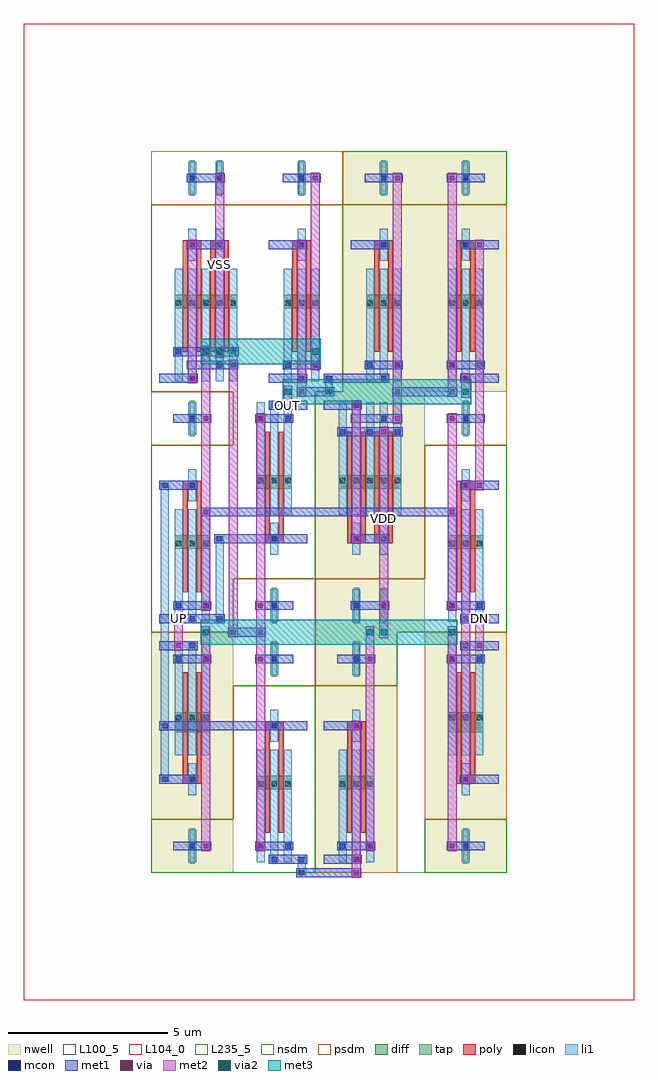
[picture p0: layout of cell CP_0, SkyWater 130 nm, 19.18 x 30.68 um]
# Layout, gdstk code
from math import pi, radians
import gdstk
lib = gdstk.Library(unit=1e-6, precision=1e-09)
def R(c, l, rs):  # rectangles x0, y0, x1, y1
    for r in rs: c.add(gdstk.rectangle(r[:2], r[2:], *l))
def A(c, l, x, y, w, h, nx, ny, dx, dy):  # array of equal rectangles
    R(c, l, [(x+i*dx, y+j*dy, x+i*dx+w, y+j*dy+h) for i in range(nx) for j in range(ny)])
def P(c, l, *ps):  # polygons
    for p in ps: c.add(gdstk.Polygon(p, *l))
nwell = (64, 20)
diff = (65, 20)
tap = (65, 44)
poly = (66, 20)
licon = (66, 44)
li1 = (67, 20)
mcon = (67, 44)
met1 = (68, 20)
via = (68, 44)
met2 = (69, 20)
via2 = (69, 44)
met3 = (70, 20)
nsdm = (93, 44)
psdm = (94, 20)
L100_5 = (100, 5)
L104_0 = (104, 0)
L235_5 = (235, 5)

scm_nmos_16357927_x1_y1_ = lib.new_cell('SCM_NMOS_16357927_X1_Y1_1668766171')
R(scm_nmos_16357927_x1_y1_, diff, [(0.735,2.625,2.705,3.045)])
R(scm_nmos_16357927_x1_y1_, tap, [(1.205,6.16,1.375,7.28), (2.065,6.16,2.235,7.28)])
A(scm_nmos_16357927_x1_y1_, poly, 1, 1.26, 0.15, 3.36, 4, 1, 0.43, 0)
R(scm_nmos_16357927_x1_y1_, poly, [(1,4.485,1.58,4.755), (1.86,4.485,2.44,4.755)])
A(scm_nmos_16357927_x1_y1_, licon, 0.775, 2.705, 0.17, 0.17, 3, 1, 0.43, 0)
A(scm_nmos_16357927_x1_y1_, licon, 1.635, 2.705, 0.17, 0.17, 3, 1, 0.43, 0)
R(scm_nmos_16357927_x1_y1_, licon, [(1.205,4.535,1.375,4.705), (2.065,4.535,2.235,4.705), (1.205,6.635,1.375,6.805), (2.065,6.635,2.235,6.805)])
A(scm_nmos_16357927_x1_y1_, li1, 0.735, 0.335, 0.25, 3.53, 5, 1, 0.43, 0)
R(scm_nmos_16357927_x1_y1_, li1, [(1.165,4.115,1.415,5.125), (2.025,4.115,2.275,5.125), (1.165,6.215,1.415,7.225), (2.025,6.215,2.275,7.225)])
A(scm_nmos_16357927_x1_y1_, mcon, 0.775, 1.175, 0.17, 0.17, 3, 1, 0.86, 0)
R(scm_nmos_16357927_x1_y1_, mcon, [(1.205,0.335,1.375,0.505), (2.065,0.755,2.235,0.925), (1.205,4.535,1.375,4.705), (2.065,4.535,2.235,4.705), (1.205,6.635,1.375,6.805), (2.065,6.635,2.235,6.805)])
R(scm_nmos_16357927_x1_y1_, met1, [(0.26,0.28,1.46,0.56), (1.12,0.7,2.32,0.98), (0.69,1.12,2.75,1.4), (1.12,4.48,2.32,4.76), (1.12,6.58,2.32,6.86)])
R(scm_nmos_16357927_x1_y1_, via, [(1.215,0.345,1.365,0.495), (2.075,1.185,2.225,1.335), (1.215,4.545,1.365,4.695), (2.075,6.645,2.225,6.795)])
R(scm_nmos_16357927_x1_y1_, met2, [(1.15,0.26,1.43,4.78), (2.01,1.1,2.29,6.88)])
R(scm_nmos_16357927_x1_y1_, nsdm, [(0,0,3.44,5.88)])
R(scm_nmos_16357927_x1_y1_, psdm, [(0,5.88,3.44,7.56)])
R(scm_nmos_16357927_x1_y1_, L100_5, [(0,0,3.44,7.56)])

scm_pmos_15963850_x1_y1_ = lib.new_cell('SCM_PMOS_15963850_X1_Y1_1668766172')
R(scm_pmos_15963850_x1_y1_, nwell, [(0,0,3.44,7.56)])
R(scm_pmos_15963850_x1_y1_, diff, [(0.735,2.625,2.705,3.045)])
R(scm_pmos_15963850_x1_y1_, tap, [(1.205,6.16,1.375,7.28), (2.065,6.16,2.235,7.28)])
A(scm_pmos_15963850_x1_y1_, poly, 1, 1.26, 0.15, 3.36, 4, 1, 0.43, 0)
R(scm_pmos_15963850_x1_y1_, poly, [(1,4.485,1.58,4.755), (1.86,4.485,2.44,4.755)])
A(scm_pmos_15963850_x1_y1_, licon, 0.775, 2.705, 0.17, 0.17, 3, 1, 0.43, 0)
A(scm_pmos_15963850_x1_y1_, licon, 1.635, 2.705, 0.17, 0.17, 3, 1, 0.43, 0)
R(scm_pmos_15963850_x1_y1_, licon, [(1.205,4.535,1.375,4.705), (2.065,4.535,2.235,4.705), (1.205,6.635,1.375,6.805), (2.065,6.635,2.235,6.805)])
A(scm_pmos_15963850_x1_y1_, li1, 0.735, 0.335, 0.25, 3.53, 5, 1, 0.43, 0)
R(scm_pmos_15963850_x1_y1_, li1, [(1.165,4.115,1.415,5.125), (2.025,4.115,2.275,5.125), (1.165,6.215,1.415,7.225), (2.025,6.215,2.275,7.225)])
A(scm_pmos_15963850_x1_y1_, mcon, 0.775, 1.175, 0.17, 0.17, 3, 1, 0.86, 0)
R(scm_pmos_15963850_x1_y1_, mcon, [(1.205,0.335,1.375,0.505), (2.065,0.755,2.235,0.925), (1.205,4.535,1.375,4.705), (2.065,4.535,2.235,4.705), (1.205,6.635,1.375,6.805), (2.065,6.635,2.235,6.805)])
R(scm_pmos_15963850_x1_y1_, met1, [(0.26,0.28,1.46,0.56), (1.12,0.7,2.32,0.98), (0.69,1.12,2.75,1.4), (1.12,4.48,2.32,4.76), (1.12,6.58,2.32,6.86)])
R(scm_pmos_15963850_x1_y1_, via, [(1.215,0.345,1.365,0.495), (2.075,1.185,2.225,1.335), (1.215,4.545,1.365,4.695), (2.075,6.645,2.225,6.795)])
R(scm_pmos_15963850_x1_y1_, met2, [(1.15,0.26,1.43,4.78), (2.01,1.1,2.29,6.88)])
R(scm_pmos_15963850_x1_y1_, nsdm, [(0,5.88,3.44,7.56)])
R(scm_pmos_15963850_x1_y1_, psdm, [(0,0,3.44,5.88)])
R(scm_pmos_15963850_x1_y1_, L100_5, [(0,0,3.44,7.56)])

nmos_s_96839798_x1_y1_16 = lib.new_cell('NMOS_S_96839798_X1_Y1_1668766156_1668766163')
R(nmos_s_96839798_x1_y1_16, diff, [(0.735,2.625,1.845,3.045)])
R(nmos_s_96839798_x1_y1_16, tap, [(1.205,6.16,1.375,7.28)])
R(nmos_s_96839798_x1_y1_16, poly, [(1,1.26,1.15,4.62), (1.43,1.26,1.58,4.62), (1,4.485,1.58,4.755)])
A(nmos_s_96839798_x1_y1_16, licon, 0.775, 2.705, 0.17, 0.17, 3, 1, 0.43, 0)
R(nmos_s_96839798_x1_y1_16, licon, [(1.205,4.535,1.375,4.705), (1.205,6.635,1.375,6.805)])
A(nmos_s_96839798_x1_y1_16, li1, 0.735, 0.335, 0.25, 3.53, 3, 1, 0.43, 0)
R(nmos_s_96839798_x1_y1_16, li1, [(1.165,4.115,1.415,5.125), (1.165,6.215,1.415,7.225)])
R(nmos_s_96839798_x1_y1_16, mcon, [(1.205,0.335,1.375,0.505), (0.775,0.755,0.945,0.925), (1.635,0.755,1.805,0.925), (1.205,4.535,1.375,4.705), (1.205,6.635,1.375,6.805)])
R(nmos_s_96839798_x1_y1_16, met1, [(0.26,0.28,1.46,0.56), (0.69,0.7,1.89,0.98), (0.26,4.48,1.46,4.76), (0.69,6.58,1.89,6.86)])
R(nmos_s_96839798_x1_y1_16, via, [(1.645,0.765,1.795,0.915), (1.645,6.645,1.795,6.795)])
R(nmos_s_96839798_x1_y1_16, met2, [(1.58,0.68,1.86,6.88)])
R(nmos_s_96839798_x1_y1_16, nsdm, [(0,0,2.58,5.88)])
R(nmos_s_96839798_x1_y1_16, psdm, [(0,5.88,2.58,7.56)])
R(nmos_s_96839798_x1_y1_16, L100_5, [(0,0,2.58,7.56)])

pmos_s_93230695_x1_y1_16 = lib.new_cell('PMOS_S_93230695_X1_Y1_1668766157_1668766163')
R(pmos_s_93230695_x1_y1_16, nwell, [(0,0,2.58,7.56)])
R(pmos_s_93230695_x1_y1_16, diff, [(0.735,2.52,1.845,3.15)])
R(pmos_s_93230695_x1_y1_16, tap, [(1.205,6.16,1.375,7.28)])
R(pmos_s_93230695_x1_y1_16, poly, [(1,1.26,1.15,4.62), (1.43,1.26,1.58,4.62), (1,4.485,1.58,4.755)])
A(pmos_s_93230695_x1_y1_16, licon, 0.775, 2.6, 0.17, 0.17, 3, 1, 0.43, 0)
R(pmos_s_93230695_x1_y1_16, licon, [(1.205,4.535,1.375,4.705), (1.205,6.635,1.375,6.805)])
A(pmos_s_93230695_x1_y1_16, li1, 0.735, 0.335, 0.25, 3.53, 3, 1, 0.43, 0)
R(pmos_s_93230695_x1_y1_16, li1, [(1.165,4.115,1.415,5.125), (1.165,6.215,1.415,7.225)])
R(pmos_s_93230695_x1_y1_16, mcon, [(1.205,0.335,1.375,0.505), (0.775,0.755,0.945,0.925), (1.635,0.755,1.805,0.925), (1.205,4.535,1.375,4.705), (1.205,6.635,1.375,6.805)])
R(pmos_s_93230695_x1_y1_16, met1, [(0.26,0.28,1.46,0.56), (0.69,0.7,1.89,0.98), (0.26,4.48,1.46,4.76), (0.69,6.58,1.89,6.86)])
R(pmos_s_93230695_x1_y1_16, via, [(1.645,0.765,1.795,0.915), (1.645,6.645,1.795,6.795)])
R(pmos_s_93230695_x1_y1_16, met2, [(1.58,0.68,1.86,6.88)])
R(pmos_s_93230695_x1_y1_16, nsdm, [(0,5.88,2.58,7.56)])
R(pmos_s_93230695_x1_y1_16, psdm, [(0,0,2.58,5.88)])
R(pmos_s_93230695_x1_y1_16, L100_5, [(0,0,2.58,7.56)])

inv_92586643_0_0_1668766 = lib.new_cell('INV_92586643_0_0_1668766163')
R(inv_92586643_0_0_1668766, li1, [(2.025,2.855,2.275,3.025), (2.025,2.855,2.275,3.025), (2.025,2.94,2.275,12.18), (2.025,12.095,2.275,12.265), (2.025,12.095,2.275,12.265)])
R(inv_92586643_0_0_1668766, mcon, [(2.065,2.855,2.235,3.025), (2.065,2.855,2.235,3.025), (2.065,12.095,2.235,12.265), (2.065,12.095,2.235,12.265)])
R(inv_92586643_0_0_1668766, met1, [(1.98,2.8,2.32,3.08), (1.98,2.8,2.32,3.08), (1.56,7,1.88,7.28), (1.56,7,1.88,7.28), (1.56,7.84,1.88,8.12), (1.56,7.84,1.88,8.12), (1.98,12.04,2.32,12.32), (1.98,12.04,2.32,12.32)])
P(inv_92586643_0_0_1668766, met1, [(0,0),(0,0),(0,0),(0,0)],
  [(0,0),(0,0),(0,0),(0,0)],
  [(0,0),(0,0),(0,0),(0,0)],
  [(0,0),(0,0),(0,0),(0,0)])
R(inv_92586643_0_0_1668766, via, [(1.645,7.065,1.795,7.215), (1.645,7.065,1.795,7.215), (1.645,7.905,1.795,8.055), (1.645,7.905,1.795,8.055)])
R(inv_92586643_0_0_1668766, met2, [(1.58,6.98,1.86,7.3), (1.58,6.98,1.86,7.3), (1.58,7.14,1.86,7.98), (1.58,7.82,1.86,8.14), (1.58,7.82,1.86,8.14)])
P(inv_92586643_0_0_1668766, met2, [(0,0),(0,0),(0,0),(0,0)],
  [(0,0),(0,0),(0,0),(0,0)])
R(inv_92586643_0_0_1668766, L235_5, [(0,0,2.58,15.12)])
inv_92586643_0_0_1668766.add(gdstk.Reference(nmos_s_96839798_x1_y1_16, (2.58,7.56), rotation=pi))
inv_92586643_0_0_1668766.add(gdstk.Reference(pmos_s_93230695_x1_y1_16, (2.58,7.56), rotation=pi, x_reflection=True))

c_nmos_s_96839798_x1_y1_16 = lib.new_cell('NMOS_S_96839798_X1_Y1_1668766157_1668766164')
R(c_nmos_s_96839798_x1_y1_16, diff, [(0.735,2.625,1.845,3.045)])
R(c_nmos_s_96839798_x1_y1_16, tap, [(1.205,6.16,1.375,7.28)])
R(c_nmos_s_96839798_x1_y1_16, poly, [(1,1.26,1.15,4.62), (1.43,1.26,1.58,4.62), (1,4.485,1.58,4.755)])
A(c_nmos_s_96839798_x1_y1_16, licon, 0.775, 2.705, 0.17, 0.17, 3, 1, 0.43, 0)
R(c_nmos_s_96839798_x1_y1_16, licon, [(1.205,4.535,1.375,4.705), (1.205,6.635,1.375,6.805)])
A(c_nmos_s_96839798_x1_y1_16, li1, 0.735, 0.335, 0.25, 3.53, 3, 1, 0.43, 0)
R(c_nmos_s_96839798_x1_y1_16, li1, [(1.165,4.115,1.415,5.125), (1.165,6.215,1.415,7.225)])
R(c_nmos_s_96839798_x1_y1_16, mcon, [(1.205,0.335,1.375,0.505), (0.775,0.755,0.945,0.925), (1.635,0.755,1.805,0.925), (1.205,4.535,1.375,4.705), (1.205,6.635,1.375,6.805)])
R(c_nmos_s_96839798_x1_y1_16, met1, [(0.26,0.28,1.46,0.56), (0.69,0.7,1.89,0.98), (0.26,4.48,1.46,4.76), (0.69,6.58,1.89,6.86)])
R(c_nmos_s_96839798_x1_y1_16, via, [(1.645,0.765,1.795,0.915), (1.645,6.645,1.795,6.795)])
R(c_nmos_s_96839798_x1_y1_16, met2, [(1.58,0.68,1.86,6.88)])
R(c_nmos_s_96839798_x1_y1_16, nsdm, [(0,0,2.58,5.88)])
R(c_nmos_s_96839798_x1_y1_16, psdm, [(0,5.88,2.58,7.56)])
R(c_nmos_s_96839798_x1_y1_16, L100_5, [(0,0,2.58,7.56)])

c_pmos_s_93230695_x1_y1_16 = lib.new_cell('PMOS_S_93230695_X1_Y1_1668766158_1668766164')
R(c_pmos_s_93230695_x1_y1_16, nwell, [(0,0,2.58,7.56)])
R(c_pmos_s_93230695_x1_y1_16, diff, [(0.735,2.52,1.845,3.15)])
R(c_pmos_s_93230695_x1_y1_16, tap, [(1.205,6.16,1.375,7.28)])
R(c_pmos_s_93230695_x1_y1_16, poly, [(1,1.26,1.15,4.62), (1.43,1.26,1.58,4.62), (1,4.485,1.58,4.755)])
A(c_pmos_s_93230695_x1_y1_16, licon, 0.775, 2.6, 0.17, 0.17, 3, 1, 0.43, 0)
R(c_pmos_s_93230695_x1_y1_16, licon, [(1.205,4.535,1.375,4.705), (1.205,6.635,1.375,6.805)])
A(c_pmos_s_93230695_x1_y1_16, li1, 0.735, 0.335, 0.25, 3.53, 3, 1, 0.43, 0)
R(c_pmos_s_93230695_x1_y1_16, li1, [(1.165,4.115,1.415,5.125), (1.165,6.215,1.415,7.225)])
R(c_pmos_s_93230695_x1_y1_16, mcon, [(1.205,0.335,1.375,0.505), (0.775,0.755,0.945,0.925), (1.635,0.755,1.805,0.925), (1.205,4.535,1.375,4.705), (1.205,6.635,1.375,6.805)])
R(c_pmos_s_93230695_x1_y1_16, met1, [(0.26,0.28,1.46,0.56), (0.69,0.7,1.89,0.98), (0.26,4.48,1.46,4.76), (0.69,6.58,1.89,6.86)])
R(c_pmos_s_93230695_x1_y1_16, via, [(1.645,0.765,1.795,0.915), (1.645,6.645,1.795,6.795)])
R(c_pmos_s_93230695_x1_y1_16, met2, [(1.58,0.68,1.86,6.88)])
R(c_pmos_s_93230695_x1_y1_16, nsdm, [(0,5.88,2.58,7.56)])
R(c_pmos_s_93230695_x1_y1_16, psdm, [(0,0,2.58,5.88)])
R(c_pmos_s_93230695_x1_y1_16, L100_5, [(0,0,2.58,7.56)])

inv_92586643_1_0_1668766 = lib.new_cell('INV_92586643_1_0_1668766164')
R(inv_92586643_1_0_1668766, met1, [(1.13,2.8,1.45,3.08), (1.13,2.8,1.45,3.08), (1.56,7,1.88,7.28), (1.56,7,1.88,7.28), (1.56,7.84,1.88,8.12), (1.56,7.84,1.88,8.12), (1.13,12.04,1.45,12.32), (1.13,12.04,1.45,12.32)])
P(inv_92586643_1_0_1668766, met1, [(0,0),(0,0),(0,0),(0,0)],
  [(0,0),(0,0),(0,0),(0,0)],
  [(0,0),(0,0),(0,0),(0,0)],
  [(0,0),(0,0),(0,0),(0,0)])
R(inv_92586643_1_0_1668766, via, [(1.215,2.865,1.365,3.015), (1.215,2.865,1.365,3.015), (1.645,7.065,1.795,7.215), (1.645,7.065,1.795,7.215), (1.645,7.905,1.795,8.055), (1.645,7.905,1.795,8.055), (1.215,12.105,1.365,12.255), (1.215,12.105,1.365,12.255)])
R(inv_92586643_1_0_1668766, met2, [(1.15,2.78,1.43,3.1), (1.15,2.78,1.43,3.1), (1.15,2.94,1.43,12.18), (1.58,6.98,1.86,7.3), (1.58,6.98,1.86,7.3), (1.58,7.14,1.86,7.98), (1.58,7.82,1.86,8.14), (1.58,7.82,1.86,8.14), (1.15,12.02,1.43,12.34), (1.15,12.02,1.43,12.34)])
P(inv_92586643_1_0_1668766, met2, [(0,0),(0,0),(0,0),(0,0)],
  [(0,0),(0,0),(0,0),(0,0)])
R(inv_92586643_1_0_1668766, L235_5, [(0,0,2.58,15.12)])
inv_92586643_1_0_1668766.add(gdstk.Reference(c_nmos_s_96839798_x1_y1_16, (2.58,7.56), rotation=pi))
inv_92586643_1_0_1668766.add(gdstk.Reference(c_pmos_s_93230695_x1_y1_16, (2.58,7.56), rotation=pi, x_reflection=True))

dcl_nmos_s_62101695_x1_y = lib.new_cell('DCL_NMOS_S_62101695_X1_Y1_1668766165')
R(dcl_nmos_s_62101695_x1_y, diff, [(0.735,2.625,1.845,3.045)])
R(dcl_nmos_s_62101695_x1_y, tap, [(1.205,6.16,1.375,7.28)])
R(dcl_nmos_s_62101695_x1_y, poly, [(1,1.26,1.15,4.62), (1.43,1.26,1.58,4.62), (1,4.485,1.58,4.755)])
A(dcl_nmos_s_62101695_x1_y, licon, 0.775, 2.705, 0.17, 0.17, 3, 1, 0.43, 0)
R(dcl_nmos_s_62101695_x1_y, licon, [(1.205,4.535,1.375,4.705), (1.205,6.635,1.375,6.805)])
A(dcl_nmos_s_62101695_x1_y, li1, 0.735, 0.335, 0.25, 3.53, 3, 1, 0.43, 0)
R(dcl_nmos_s_62101695_x1_y, li1, [(1.165,4.115,1.415,5.125), (1.165,6.215,1.415,7.225)])
R(dcl_nmos_s_62101695_x1_y, mcon, [(1.205,0.335,1.375,0.505), (0.775,0.755,0.945,0.925), (1.635,0.755,1.805,0.925), (1.205,4.535,1.375,4.705), (1.205,6.635,1.375,6.805)])
R(dcl_nmos_s_62101695_x1_y, met1, [(0.26,0.28,1.46,0.56), (0.69,0.7,1.89,0.98), (0.26,4.48,1.46,4.76), (0.69,6.58,1.89,6.86)])
R(dcl_nmos_s_62101695_x1_y, via, [(1.215,0.345,1.365,0.495), (1.645,0.765,1.795,0.915), (1.215,4.545,1.365,4.695), (1.645,6.645,1.795,6.795)])
R(dcl_nmos_s_62101695_x1_y, met2, [(1.15,0.26,1.43,4.78), (1.58,0.68,1.86,6.88)])
R(dcl_nmos_s_62101695_x1_y, nsdm, [(0,0,2.58,5.88)])
R(dcl_nmos_s_62101695_x1_y, psdm, [(0,5.88,2.58,7.56)])
R(dcl_nmos_s_62101695_x1_y, L100_5, [(0,0,2.58,7.56)])

dcl_pmos_s_57934405_x1_y = lib.new_cell('DCL_PMOS_S_57934405_X1_Y1_1668766166')
R(dcl_pmos_s_57934405_x1_y, nwell, [(0,0,2.58,7.56)])
R(dcl_pmos_s_57934405_x1_y, diff, [(0.735,2.625,1.845,3.045)])
R(dcl_pmos_s_57934405_x1_y, tap, [(1.205,6.16,1.375,7.28)])
R(dcl_pmos_s_57934405_x1_y, poly, [(1,1.26,1.15,4.62), (1.43,1.26,1.58,4.62), (1,4.485,1.58,4.755)])
A(dcl_pmos_s_57934405_x1_y, licon, 0.775, 2.705, 0.17, 0.17, 3, 1, 0.43, 0)
R(dcl_pmos_s_57934405_x1_y, licon, [(1.205,4.535,1.375,4.705), (1.205,6.635,1.375,6.805)])
A(dcl_pmos_s_57934405_x1_y, li1, 0.735, 0.335, 0.25, 3.53, 3, 1, 0.43, 0)
R(dcl_pmos_s_57934405_x1_y, li1, [(1.165,4.115,1.415,5.125), (1.165,6.215,1.415,7.225)])
R(dcl_pmos_s_57934405_x1_y, mcon, [(1.205,0.335,1.375,0.505), (0.775,0.755,0.945,0.925), (1.635,0.755,1.805,0.925), (1.205,4.535,1.375,4.705), (1.205,6.635,1.375,6.805)])
R(dcl_pmos_s_57934405_x1_y, met1, [(0.26,0.28,1.46,0.56), (0.69,0.7,1.89,0.98), (0.26,4.48,1.46,4.76), (0.69,6.58,1.89,6.86)])
R(dcl_pmos_s_57934405_x1_y, via, [(1.215,0.345,1.365,0.495), (1.645,0.765,1.795,0.915), (1.215,4.545,1.365,4.695), (1.645,6.645,1.795,6.795)])
R(dcl_pmos_s_57934405_x1_y, met2, [(1.15,0.26,1.43,4.78), (1.58,0.68,1.86,6.88)])
R(dcl_pmos_s_57934405_x1_y, nsdm, [(0,5.88,2.58,7.56)])
R(dcl_pmos_s_57934405_x1_y, psdm, [(0,0,2.58,5.88)])
R(dcl_pmos_s_57934405_x1_y, L100_5, [(0,0,2.58,7.56)])

nmos_s_58782418_x1_y1_16 = lib.new_cell('NMOS_S_58782418_X1_Y1_1668766167')
R(nmos_s_58782418_x1_y1_16, diff, [(0.735,2.625,1.845,3.045)])
R(nmos_s_58782418_x1_y1_16, tap, [(1.205,6.16,1.375,7.28)])
R(nmos_s_58782418_x1_y1_16, poly, [(1,1.26,1.15,4.62), (1.43,1.26,1.58,4.62), (1,4.485,1.58,4.755)])
A(nmos_s_58782418_x1_y1_16, licon, 0.775, 2.705, 0.17, 0.17, 3, 1, 0.43, 0)
R(nmos_s_58782418_x1_y1_16, licon, [(1.205,4.535,1.375,4.705), (1.205,6.635,1.375,6.805)])
A(nmos_s_58782418_x1_y1_16, li1, 0.735, 0.335, 0.25, 3.53, 3, 1, 0.43, 0)
R(nmos_s_58782418_x1_y1_16, li1, [(1.165,4.115,1.415,5.125), (1.165,6.215,1.415,7.225)])
R(nmos_s_58782418_x1_y1_16, mcon, [(1.205,0.335,1.375,0.505), (0.775,0.755,0.945,0.925), (1.635,0.755,1.805,0.925), (1.205,4.535,1.375,4.705), (1.205,6.635,1.375,6.805)])
R(nmos_s_58782418_x1_y1_16, met1, [(0.26,0.28,1.46,0.56), (0.69,0.7,1.89,0.98), (0.26,4.48,1.46,4.76), (0.69,6.58,1.89,6.86)])
R(nmos_s_58782418_x1_y1_16, via, [(1.645,0.765,1.795,0.915), (1.645,6.645,1.795,6.795)])
R(nmos_s_58782418_x1_y1_16, met2, [(1.58,0.68,1.86,6.88)])
R(nmos_s_58782418_x1_y1_16, nsdm, [(0,0,2.58,5.88)])
R(nmos_s_58782418_x1_y1_16, psdm, [(0,5.88,2.58,7.56)])
R(nmos_s_58782418_x1_y1_16, L100_5, [(0,0,2.58,7.56)])

c_nmos_s_96839798_x1_y1_16_ = lib.new_cell('NMOS_S_96839798_X1_Y1_1668766168')
R(c_nmos_s_96839798_x1_y1_16_, diff, [(0.735,2.625,1.845,3.045)])
R(c_nmos_s_96839798_x1_y1_16_, tap, [(1.205,6.16,1.375,7.28)])
R(c_nmos_s_96839798_x1_y1_16_, poly, [(1,1.26,1.15,4.62), (1.43,1.26,1.58,4.62), (1,4.485,1.58,4.755)])
A(c_nmos_s_96839798_x1_y1_16_, licon, 0.775, 2.705, 0.17, 0.17, 3, 1, 0.43, 0)
R(c_nmos_s_96839798_x1_y1_16_, licon, [(1.205,4.535,1.375,4.705), (1.205,6.635,1.375,6.805)])
A(c_nmos_s_96839798_x1_y1_16_, li1, 0.735, 0.335, 0.25, 3.53, 3, 1, 0.43, 0)
R(c_nmos_s_96839798_x1_y1_16_, li1, [(1.165,4.115,1.415,5.125), (1.165,6.215,1.415,7.225)])
R(c_nmos_s_96839798_x1_y1_16_, mcon, [(1.205,0.335,1.375,0.505), (0.775,0.755,0.945,0.925), (1.635,0.755,1.805,0.925), (1.205,4.535,1.375,4.705), (1.205,6.635,1.375,6.805)])
R(c_nmos_s_96839798_x1_y1_16_, met1, [(0.26,0.28,1.46,0.56), (0.69,0.7,1.89,0.98), (0.26,4.48,1.46,4.76), (0.69,6.58,1.89,6.86)])
R(c_nmos_s_96839798_x1_y1_16_, via, [(1.645,0.765,1.795,0.915), (1.645,6.645,1.795,6.795)])
R(c_nmos_s_96839798_x1_y1_16_, met2, [(1.58,0.68,1.86,6.88)])
R(c_nmos_s_96839798_x1_y1_16_, nsdm, [(0,0,2.58,5.88)])
R(c_nmos_s_96839798_x1_y1_16_, psdm, [(0,5.88,2.58,7.56)])
R(c_nmos_s_96839798_x1_y1_16_, L100_5, [(0,0,2.58,7.56)])

pmos_s_48783884_x1_y1_16 = lib.new_cell('PMOS_S_48783884_X1_Y1_1668766169')
R(pmos_s_48783884_x1_y1_16, nwell, [(0,0,2.58,7.56)])
R(pmos_s_48783884_x1_y1_16, diff, [(0.735,2.625,1.845,3.045)])
R(pmos_s_48783884_x1_y1_16, tap, [(1.205,6.16,1.375,7.28)])
R(pmos_s_48783884_x1_y1_16, poly, [(1,1.26,1.15,4.62), (1.43,1.26,1.58,4.62), (1,4.485,1.58,4.755)])
A(pmos_s_48783884_x1_y1_16, licon, 0.775, 2.705, 0.17, 0.17, 3, 1, 0.43, 0)
R(pmos_s_48783884_x1_y1_16, licon, [(1.205,4.535,1.375,4.705), (1.205,6.635,1.375,6.805)])
A(pmos_s_48783884_x1_y1_16, li1, 0.735, 0.335, 0.25, 3.53, 3, 1, 0.43, 0)
R(pmos_s_48783884_x1_y1_16, li1, [(1.165,4.115,1.415,5.125), (1.165,6.215,1.415,7.225)])
R(pmos_s_48783884_x1_y1_16, mcon, [(1.205,0.335,1.375,0.505), (0.775,0.755,0.945,0.925), (1.635,0.755,1.805,0.925), (1.205,4.535,1.375,4.705), (1.205,6.635,1.375,6.805)])
R(pmos_s_48783884_x1_y1_16, met1, [(0.26,0.28,1.46,0.56), (0.69,0.7,1.89,0.98), (0.26,4.48,1.46,4.76), (0.69,6.58,1.89,6.86)])
R(pmos_s_48783884_x1_y1_16, via, [(1.645,0.765,1.795,0.915), (1.645,6.645,1.795,6.795)])
R(pmos_s_48783884_x1_y1_16, met2, [(1.58,0.68,1.86,6.88)])
R(pmos_s_48783884_x1_y1_16, nsdm, [(0,5.88,2.58,7.56)])
R(pmos_s_48783884_x1_y1_16, psdm, [(0,0,2.58,5.88)])
R(pmos_s_48783884_x1_y1_16, L100_5, [(0,0,2.58,7.56)])

pmos_s_63670781_x1_y1_16 = lib.new_cell('PMOS_S_63670781_X1_Y1_1668766170')
R(pmos_s_63670781_x1_y1_16, nwell, [(0,0,2.58,7.56)])
R(pmos_s_63670781_x1_y1_16, diff, [(0.735,2.625,1.845,3.045)])
R(pmos_s_63670781_x1_y1_16, tap, [(1.205,6.16,1.375,7.28)])
R(pmos_s_63670781_x1_y1_16, poly, [(1,1.26,1.15,4.62), (1.43,1.26,1.58,4.62), (1,4.485,1.58,4.755)])
A(pmos_s_63670781_x1_y1_16, licon, 0.775, 2.705, 0.17, 0.17, 3, 1, 0.43, 0)
R(pmos_s_63670781_x1_y1_16, licon, [(1.205,4.535,1.375,4.705), (1.205,6.635,1.375,6.805)])
A(pmos_s_63670781_x1_y1_16, li1, 0.735, 0.335, 0.25, 3.53, 3, 1, 0.43, 0)
R(pmos_s_63670781_x1_y1_16, li1, [(1.165,4.115,1.415,5.125), (1.165,6.215,1.415,7.225)])
R(pmos_s_63670781_x1_y1_16, mcon, [(1.205,0.335,1.375,0.505), (0.775,0.755,0.945,0.925), (1.635,0.755,1.805,0.925), (1.205,4.535,1.375,4.705), (1.205,6.635,1.375,6.805)])
R(pmos_s_63670781_x1_y1_16, met1, [(0.26,0.28,1.46,0.56), (0.69,0.7,1.89,0.98), (0.26,4.48,1.46,4.76), (0.69,6.58,1.89,6.86)])
R(pmos_s_63670781_x1_y1_16, via, [(1.645,0.765,1.795,0.915), (1.645,6.645,1.795,6.795)])
R(pmos_s_63670781_x1_y1_16, met2, [(1.58,0.68,1.86,6.88)])
R(pmos_s_63670781_x1_y1_16, nsdm, [(0,5.88,2.58,7.56)])
R(pmos_s_63670781_x1_y1_16, psdm, [(0,0,2.58,5.88)])
R(pmos_s_63670781_x1_y1_16, L100_5, [(0,0,2.58,7.56)])

cp_0 = lib.new_cell('CP_0')
R(cp_0, li1, [(4.605,-0.085,4.855,0.085), (4.605,-0.085,4.855,0.085), (4.605,0,4.855,0.42), (4.605,0.335,4.855,0.505), (4.605,0.335,4.855,0.505), (0.305,4.535,0.555,4.705), (0.305,4.535,0.555,4.705), (2.025,7.895,2.275,8.065), (2.025,7.895,2.275,8.065), (2.025,7.98,2.275,10.5), (2.025,10.415,2.275,10.585), (2.025,10.415,2.275,10.585), (5.465,15.035,5.715,15.205), (5.465,15.035,5.715,15.205), (5.465,15.12,5.715,15.54), (5.465,15.455,5.715,15.625), (5.465,15.455,5.715,15.625)])
P(cp_0, li1, [(0,0),(0,0),(0,0),(0,0)])
R(cp_0, mcon, [(4.645,-0.085,4.815,0.085), (4.645,-0.085,4.815,0.085), (4.645,0.335,4.815,0.505), (4.645,0.335,4.815,0.505), (0.345,4.535,0.515,4.705), (0.345,4.535,0.515,4.705), (2.065,7.895,2.235,8.065), (2.065,7.895,2.235,8.065), (2.065,10.415,2.235,10.585), (2.065,10.415,2.235,10.585), (5.505,15.035,5.675,15.205), (5.505,15.035,5.675,15.205), (5.505,15.455,5.675,15.625), (5.505,15.455,5.675,15.625)])
R(cp_0, met1, [(4.56,-0.14,4.9,0.14), (4.56,-0.14,4.9,0.14), (4.73,-0.14,6.45,0.14), (6.29,-0.14,6.61,0.14), (6.29,-0.14,6.61,0.14), (4.56,0.28,4.9,0.56), (4.56,0.28,4.9,0.56), (0.26,4.48,0.6,4.76), (0.26,4.48,0.6,4.76), (0.43,4.48,3.87,4.76), (2.42,7.42,2.74,7.7), (2.42,7.42,2.74,7.7), (2.42,7.42,2.74,7.7), (2.42,7.42,2.74,7.7), (2.58,7.42,3.44,7.7), (3.28,7.42,3.6,7.7), (3.28,7.42,3.6,7.7), (3.28,7.42,3.6,7.7), (3.28,7.42,3.6,7.7), (1.29,7.84,2.15,8.12), (1.98,7.84,2.32,8.12), (1.98,7.84,2.32,8.12), (1.98,10.36,2.32,10.64), (1.98,10.36,2.32,10.64), (2.15,10.36,3.87,10.64), (1.56,11.2,1.88,11.48), (1.56,11.2,1.88,11.48), (1.56,11.2,1.88,11.48), (1.56,11.2,1.88,11.48), (1.72,11.2,9.46,11.48), (9.3,11.2,9.62,11.48), (9.3,11.2,9.62,11.48), (9.3,11.2,9.62,11.48), (9.3,11.2,9.62,11.48), (10.16,12.04,10.48,12.32), (10.16,12.04,10.48,12.32), (7.31,14.14,7.74,14.42), (7.58,14.14,7.9,14.42), (7.58,14.14,7.9,14.42), (7.58,14.14,7.9,14.42), (7.58,14.14,7.9,14.42), (4.14,14.56,4.46,14.84), (4.14,14.56,4.46,14.84), (4.57,14.98,4.89,15.26), (4.57,14.98,4.89,15.26), (4.73,14.98,5.59,15.26), (5.42,14.98,5.76,15.26), (5.42,14.98,5.76,15.26), (7.58,14.98,7.9,15.26), (7.58,14.98,7.9,15.26), (7.58,14.98,7.9,15.26), (7.58,14.98,7.9,15.26), (7.74,14.98,9.46,15.26), (9.3,14.98,9.62,15.26), (9.3,14.98,9.62,15.26), (9.3,14.98,9.62,15.26), (9.3,14.98,9.62,15.26), (5.42,15.4,5.76,15.68), (5.42,15.4,5.76,15.68), (5.59,15.4,6.45,15.68), (9.73,15.4,10.05,15.68), (9.73,15.4,10.05,15.68), (2.15,15.82,2.58,16.1), (2.42,15.82,2.74,16.1), (2.42,15.82,2.74,16.1), (2.42,15.82,2.74,16.1), (2.42,15.82,2.74,16.1), (10.16,19.6,10.48,19.88), (10.16,19.6,10.48,19.88)])
P(cp_0, met1, [(0,0),(0,0),(0,0),(0,0)],
  [(0,0),(0,0),(0,0),(0,0)],
  [(0,0),(0,0),(0,0),(0,0)],
  [(0,0),(0,0),(0,0),(0,0)],
  [(0,0),(0,0),(0,0),(0,0)],
  [(0,0),(0,0),(0,0),(0,0)],
  [(0,0),(0,0),(0,0),(0,0)],
  [(0,0),(0,0),(0,0),(0,0)],
  [(0,0),(0,0),(0,0),(0,0)],
  [(0,0),(0,0),(0,0),(0,0)],
  [(0,0),(0,0),(0,0),(0,0)],
  [(0,0),(0,0),(0,0),(0,0)],
  [(0,0),(0,0),(0,0),(0,0)],
  [(0,0),(0,0),(0,0),(0,0)],
  [(0,0),(0,0),(0,0),(0,0)],
  [(0,0),(0,0),(0,0),(0,0)],
  [(0,0),(0,0),(0,0),(0,0)],
  [(0,0),(0,0),(0,0),(0,0)],
  [(0,0),(0,0),(0,0),(0,0)],
  [(0,0),(0,0),(0,0),(0,0)],
  [(0,0),(0,0),(0,0),(0,0)],
  [(0,0),(0,0),(0,0),(0,0)],
  [(0,0),(0,0),(0,0),(0,0)],
  [(0,0),(0,0),(0,0),(0,0)],
  [(0,0),(0,0),(0,0),(0,0)],
  [(0,0),(0,0),(0,0),(0,0)],
  [(0,0),(0,0),(0,0),(0,0)],
  [(0,0),(0,0),(0,0),(0,0)],
  [(0,0),(0,0),(0,0),(0,0)])
R(cp_0, via, [(6.375,-0.075,6.525,0.075), (6.375,-0.075,6.525,0.075), (2.505,7.485,2.655,7.635), (2.505,7.485,2.655,7.635), (2.505,7.485,2.655,7.635), (2.505,7.485,2.655,7.635), (3.365,7.485,3.515,7.635), (3.365,7.485,3.515,7.635), (3.365,7.485,3.515,7.635), (3.365,7.485,3.515,7.635), (1.645,11.265,1.795,11.415), (1.645,11.265,1.795,11.415), (1.645,11.265,1.795,11.415), (1.645,11.265,1.795,11.415), (9.385,11.265,9.535,11.415), (9.385,11.265,9.535,11.415), (9.385,11.265,9.535,11.415), (9.385,11.265,9.535,11.415), (10.245,12.105,10.395,12.255), (10.245,12.105,10.395,12.255), (7.665,14.205,7.815,14.355), (7.665,14.205,7.815,14.355), (7.665,14.205,7.815,14.355), (7.665,14.205,7.815,14.355), (4.225,14.625,4.375,14.775), (4.225,14.625,4.375,14.775), (4.655,15.045,4.805,15.195), (4.655,15.045,4.805,15.195), (7.665,15.045,7.815,15.195), (7.665,15.045,7.815,15.195), (7.665,15.045,7.815,15.195), (7.665,15.045,7.815,15.195), (9.385,15.045,9.535,15.195), (9.385,15.045,9.535,15.195), (9.385,15.045,9.535,15.195), (9.385,15.045,9.535,15.195), (9.815,15.465,9.965,15.615), (9.815,15.465,9.965,15.615), (2.505,15.885,2.655,16.035), (2.505,15.885,2.655,16.035), (2.505,15.885,2.655,16.035), (2.505,15.885,2.655,16.035), (10.245,19.665,10.395,19.815), (10.245,19.665,10.395,19.815)])
R(cp_0, met2, [(6.31,-0.16,6.59,0.16), (6.31,-0.16,6.59,0.16), (6.31,0,6.59,0.42), (1.58,6.72,1.86,7.56), (3.3,6.72,3.58,7.56), (6.74,6.72,7.02,7.56), (9.32,6.72,9.6,7.56), (1.58,7.375,1.86,7.745), (1.58,7.375,1.86,7.745), (1.58,7.375,1.86,7.745), (1.58,7.375,1.86,7.745), (1.58,7.375,1.86,7.745), (1.58,7.375,1.86,7.745), (6.74,7.375,7.02,7.745), (6.74,7.375,7.02,7.745), (7.17,7.375,7.45,7.745), (7.17,7.375,7.45,7.745), (7.17,7.375,7.45,7.745), (7.17,7.375,7.45,7.745), (7.17,7.375,7.45,7.745), (7.17,7.375,7.45,7.745), (9.32,7.375,9.6,7.745), (9.32,7.375,9.6,7.745), (9.32,7.375,9.6,7.745), (9.32,7.375,9.6,7.745), (2.44,7.4,2.72,7.72), (2.44,7.4,2.72,7.72), (2.44,7.4,2.72,7.72), (2.44,7.4,2.72,7.72), (3.3,7.4,3.58,7.72), (3.3,7.4,3.58,7.72), (3.3,7.4,3.58,7.72), (3.3,7.4,3.58,7.72), (2.44,7.56,2.72,15.96), (3.3,7.56,3.58,8.4), (7.17,7.56,7.45,8.4), (1.58,11.18,1.86,11.5), (1.58,11.18,1.86,11.5), (1.58,11.18,1.86,11.5), (1.58,11.18,1.86,11.5), (9.32,11.18,9.6,11.5), (9.32,11.18,9.6,11.5), (9.32,11.18,9.6,11.5), (9.32,11.18,9.6,11.5), (10.18,12.02,10.46,12.34), (10.18,12.02,10.46,12.34), (10.18,12.18,10.46,19.74), (7.6,14.12,7.88,14.44), (7.6,14.12,7.88,14.44), (7.6,14.12,7.88,14.44), (7.6,14.12,7.88,14.44), (1.58,14.28,1.86,16.38), (7.6,14.28,7.88,15.12), (4.16,14.54,4.44,14.86), (4.16,14.54,4.44,14.86), (4.16,14.7,4.44,15.12), (4.16,14.935,4.44,15.305), (4.16,14.935,4.44,15.305), (9.75,14.935,10.03,15.305), (9.75,14.935,10.03,15.305), (4.59,14.96,4.87,15.28), (4.59,14.96,4.87,15.28), (7.6,14.96,7.88,15.28), (7.6,14.96,7.88,15.28), (7.6,14.96,7.88,15.28), (7.6,14.96,7.88,15.28), (9.32,14.96,9.6,15.28), (9.32,14.96,9.6,15.28), (9.32,14.96,9.6,15.28), (9.32,14.96,9.6,15.28), (4.59,15.12,4.87,15.54), (7.6,15.12,7.88,15.96), (9.32,15.12,9.6,15.96), (9.75,15.12,10.03,15.54), (9.75,15.38,10.03,15.7), (9.75,15.38,10.03,15.7), (2.44,15.8,2.72,16.12), (2.44,15.8,2.72,16.12), (2.44,15.8,2.72,16.12), (2.44,15.8,2.72,16.12), (1.58,16.195,1.86,16.565), (1.58,16.195,1.86,16.565), (1.58,16.195,1.86,16.565), (1.58,16.195,1.86,16.565), (1.58,16.195,1.86,16.565), (1.58,16.195,1.86,16.565), (2.01,16.195,2.29,16.565), (2.01,16.195,2.29,16.565), (2.01,16.195,2.29,16.565), (2.01,16.195,2.29,16.565), (2.01,16.195,2.29,16.565), (2.01,16.195,2.29,16.565), (5.02,16.195,5.3,16.565), (5.02,16.195,5.3,16.565), (10.18,19.58,10.46,19.9), (10.18,19.58,10.46,19.9)])
P(cp_0, met2, [(0,0),(0,0),(0,0),(0,0)],
  [(0,0),(0,0),(0,0),(0,0)],
  [(0,0),(0,0),(0,0),(0,0)],
  [(0,0),(0,0),(0,0),(0,0)],
  [(0,0),(0,0),(0,0),(0,0)],
  [(0,0),(0,0),(0,0),(0,0)],
  [(0,0),(0,0),(0,0),(0,0)],
  [(0,0),(0,0),(0,0),(0,0)],
  [(0,0),(0,0),(0,0),(0,0)],
  [(0,0),(0,0),(0,0),(0,0)],
  [(0,0),(0,0),(0,0),(0,0)],
  [(0,0),(0,0),(0,0),(0,0)],
  [(0,0),(0,0),(0,0),(0,0)],
  [(0,0),(0,0),(0,0),(0,0)],
  [(0,0),(0,0),(0,0),(0,0)],
  [(0,0),(0,0),(0,0),(0,0)],
  [(0,0),(0,0),(0,0),(0,0)],
  [(0,0),(0,0),(0,0),(0,0)],
  [(0,0),(0,0),(0,0),(0,0)],
  [(0,0),(0,0),(0,0),(0,0)],
  [(0,0),(0,0),(0,0),(0,0)])
R(cp_0, via2, [(1.62,7.46,1.82,7.66), (1.62,7.46,1.82,7.66), (1.62,7.46,1.82,7.66), (1.62,7.46,1.82,7.66), (1.62,7.46,1.82,7.66), (1.62,7.46,1.82,7.66), (6.78,7.46,6.98,7.66), (6.78,7.46,6.98,7.66), (7.21,7.46,7.41,7.66), (7.21,7.46,7.41,7.66), (7.21,7.46,7.41,7.66), (7.21,7.46,7.41,7.66), (7.21,7.46,7.41,7.66), (7.21,7.46,7.41,7.66), (9.36,7.46,9.56,7.66), (9.36,7.46,9.56,7.66), (9.36,7.46,9.56,7.66), (9.36,7.46,9.56,7.66), (4.2,15.02,4.4,15.22), (4.2,15.02,4.4,15.22), (9.79,15.02,9.99,15.22), (9.79,15.02,9.99,15.22), (1.62,16.28,1.82,16.48), (1.62,16.28,1.82,16.48), (1.62,16.28,1.82,16.48), (1.62,16.28,1.82,16.48), (1.62,16.28,1.82,16.48), (1.62,16.28,1.82,16.48), (2.05,16.28,2.25,16.48), (2.05,16.28,2.25,16.48), (2.05,16.28,2.25,16.48), (2.05,16.28,2.25,16.48), (2.05,16.28,2.25,16.48), (2.05,16.28,2.25,16.48), (5.06,16.28,5.26,16.48), (5.06,16.28,5.26,16.48)])
R(cp_0, met3, [(1.555,7.16,1.885,7.96), (1.555,7.16,1.885,7.96), (1.555,7.16,1.885,7.96), (1.555,7.16,1.885,7.96), (1.555,7.16,1.885,7.96), (1.555,7.16,1.885,7.96), (1.72,7.16,7.31,7.96), (6.715,7.16,7.045,7.96), (6.715,7.16,7.045,7.96), (7.145,7.16,7.475,7.96), (7.145,7.16,7.475,7.96), (7.145,7.16,7.475,7.96), (7.145,7.16,7.475,7.96), (7.145,7.16,7.475,7.96), (7.145,7.16,7.475,7.96), (7.4,7.16,9.46,7.96), (9.295,7.16,9.625,7.96), (9.295,7.16,9.625,7.96), (9.295,7.16,9.625,7.96), (9.295,7.16,9.625,7.96), (4.135,14.72,4.465,15.52), (4.135,14.72,4.465,15.52), (4.3,14.72,9.89,15.52), (9.725,14.72,10.055,15.52), (9.725,14.72,10.055,15.52), (1.555,15.98,1.885,16.78), (1.555,15.98,1.885,16.78), (1.555,15.98,1.885,16.78), (1.555,15.98,1.885,16.78), (1.555,15.98,1.885,16.78), (1.555,15.98,1.885,16.78), (1.72,15.98,2.15,16.78), (1.985,15.98,2.315,16.78), (1.985,15.98,2.315,16.78), (1.985,15.98,2.315,16.78), (1.985,15.98,2.315,16.78), (1.985,15.98,2.315,16.78), (1.985,15.98,2.315,16.78), (2.15,15.98,5.16,16.78), (4.995,15.98,5.325,16.78), (4.995,15.98,5.325,16.78)])
R(cp_0, L104_0, [(-4,-4,15.18,26.68)])
R(cp_0, L235_5, [(0,0,11.18,22.68)])
cp_0.add(gdstk.Reference(scm_nmos_16357927_x1_y1_, (0,15.12)))
cp_0.add(gdstk.Reference(scm_pmos_15963850_x1_y1_, (5.16,15.12), x_reflection=True))
cp_0.add(gdstk.Reference(inv_92586643_0_0_1668766, (2.58,15.12), rotation=pi))
cp_0.add(gdstk.Reference(inv_92586643_1_0_1668766, (8.6,15.12), x_reflection=True))
cp_0.add(gdstk.Reference(dcl_nmos_s_62101695_x1_y, (3.44,15.12)))
cp_0.add(gdstk.Reference(dcl_pmos_s_57934405_x1_y, (5.16,0)))
cp_0.add(gdstk.Reference(nmos_s_58782418_x1_y1_16, (5.16,0), rotation=pi, x_reflection=True))
cp_0.add(gdstk.Reference(c_nmos_s_96839798_x1_y1_16_, (5.16,15.12), rotation=pi))
cp_0.add(gdstk.Reference(pmos_s_48783884_x1_y1_16, (11.18,15.12), rotation=pi, x_reflection=True))
cp_0.add(gdstk.Reference(pmos_s_63670781_x1_y1_16, (6.02,15.12)))
cp_0.add(gdstk.Label('VSS', (2.15,19.11), layer=69, texttype=5))
cp_0.add(gdstk.Label('VDD', (7.31,11.13), layer=69, texttype=5))
cp_0.add(gdstk.Label('UP', (0.86,7.98), layer=68, texttype=5))
cp_0.add(gdstk.Label('DN', (10.32,7.98), layer=68, texttype=5))
cp_0.add(gdstk.Label('OUT', (4.3,14.7), layer=68, texttype=5))

lib.write_gds('CP_0.gds')
